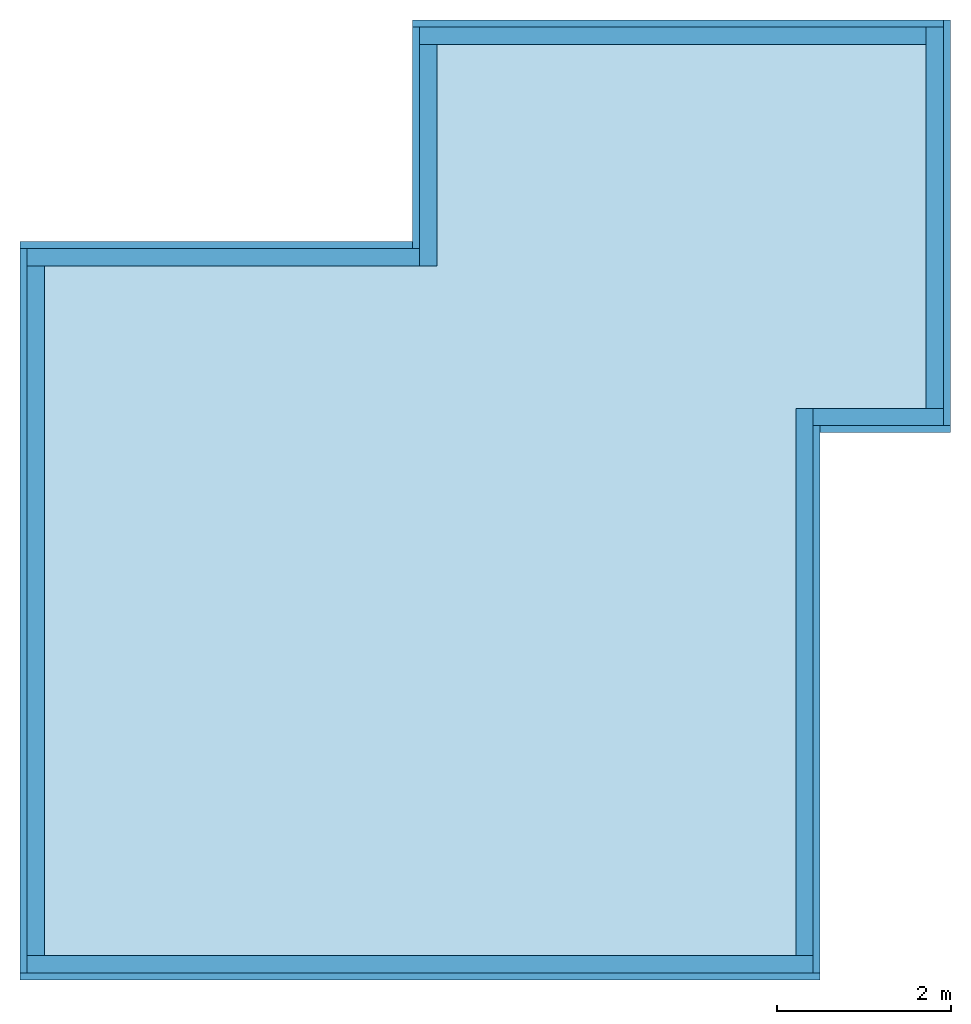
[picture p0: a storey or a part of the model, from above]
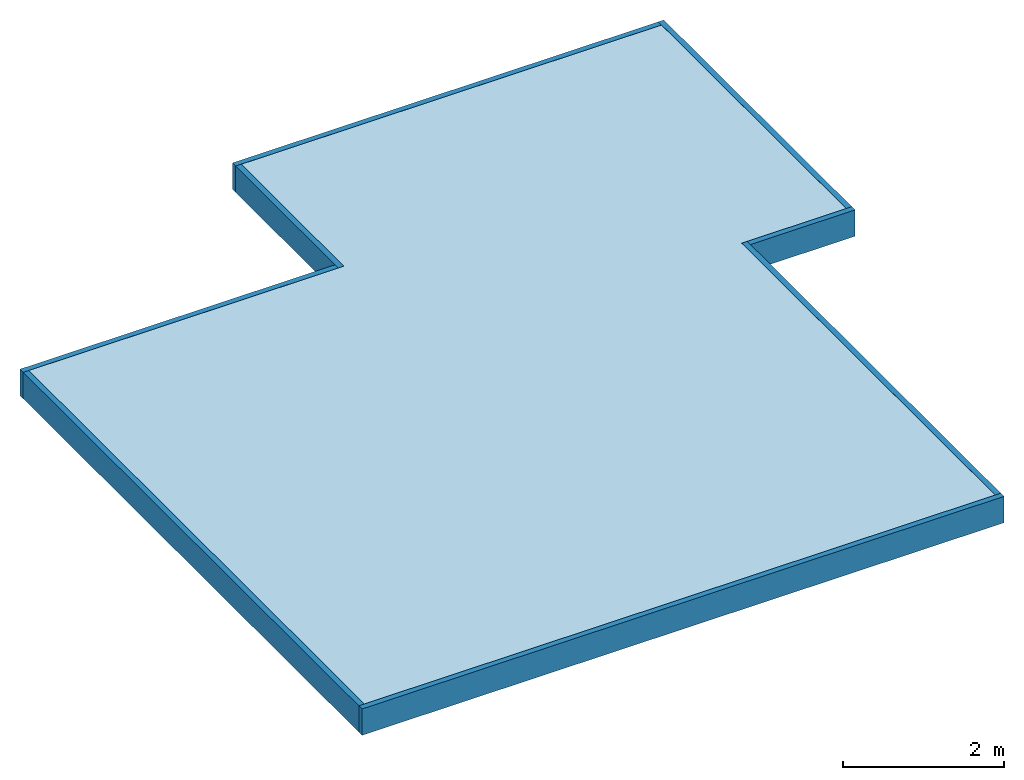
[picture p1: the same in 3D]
Properties of the parts of a building model (IFC2X3)

# File
Description: ViewDefinition [CoordinationView_V2.0, SurfaceGeometryAddOnView], Option [Drawing Scale: 50.000000], Option [Elements to export: Visible elements (on all stories)], Option [Partial Structure Display: Without Finishes], Option [IFC Domain: All], Option [Structural Function: All Elements], Option [Convert Grid elements: On], Option [Convert IFC Annotations and ARCHICAD 2D elements: Off], Option [Convert 2D symbols of Doors and Windows: Off], Option [Export geometries that Participates in Collision Detection only: On], Option [Split complex elements: Off], Option [Material Preservation: Never explode], Option [IFC Site Location: At Project Origin], Option [Curtain Wall export mode: Single Element], Option [Railing export mode: Single Element], Option [Stair export mode: Single Element], Option [Properties To Export: All properties], Option [Space containment: Off], Option [Bounding Box: Off], Option [Geometry to type objects: Off], Option [Element Properties: All], Option [Building Material Properties: Off], Option [Element Parameters: Off], Option [Component Parameters: Off], Option [IFC Base Quantities: Off], Option [Door Window Parameters: On], Option [IFC Space boundaries: Off], Option [ARCHICAD Zone Categories as IFC Space classification data: Off], Option [Element Classifications: Off]
File name: D:\Dane\Pulpit\TYMCZAAA\POINT_144_ARCH.ifc
Time: 2020-11-27T14:21:23
Author: Architect
Organization: Building Designer Office
Written by: The EXPRESS Data Manager Version 5.02.0100.09 : 26 Sep 2013
Made in: IFC file generated by GRAPHISOFT ARCHICAD 24.0.0 POL FULL Windows version (IFC add-on version: 3008 POL FULL).
Authorization: The authorising person

# IfcSite, Lokalizacja
RefLatitude: 52, 15, 0, 0; RefLongitude: 21, 0, 0, 0; RefElevation: 0 mm

# IfcBuildingStorey (4)
In: Budynek
Name | Elevation (mm)
PLATTE | -3000
EG | 0
DG | 2954
DACH | 5726

# IfcSpace: Ogólne (12)
InteriorOrExteriorSpace: INTERNAL
Pset_SpaceCommon - Category: Ogólne
AC_Pset_RenovationAndPhasing - Renovation Status: New
Name | In | _dan_NR | _dan_NAZWA | _dan_posadzka | _dan_Powierzchnia_DIN277 (m2)
 | EG | 1/1 | WC | FLIESEN | 3.93476
 | EG | 1/6 | GARDEROBE | FLIESEN | 3.60402
 | EG | 1/3 | WOHNEN-ESSEN | LAMINAT | 42.7011
 | EG | 1/4 | KÜCHE | FLIESEN | 8.137
 | EG | 1/5 | SPEIS | FLIESEN | 4.11435
 | EG | 1/7 | TECHNIKRAUM | FLIESEN | 6.52314
 | EG | 1/2 | DIELE | FLIESEN | 12.6479
 | DG | 2/5 | FLUR | TEPPICHBODEN | 8.24736
 | DG | 2/4 | BAD | FLIESEN | 8.37812
 | DG | 2/2 | ZIMMER 2 | TEPPICHBODEN | 16.068
 | DG | 2/3 | ZIMMER 3 | TEPPICHBODEN | 14.3588
 | DG | 2/1 | ZIMMER 1 | TEPPICHBODEN | 16.068

# IfcBeam: Drewno konstrukcyjne_elementy_konstrukcyjne 160 x 280 (2)
In: DACH
Material: Drewno konstrukcyjne_elementy_konstrukcyjne
_dan_Elem_Konstrukcyjny - _dan_Opis: Platew; _dan_Nazwa: Platew; _dan_Dlugosc: 10030 mm
AC_Pset_RenovationAndPhasing - Renovation Status: New
Pset_BeamCommon - Reference: Drewno konstrukcyjne_elementy_konstrukcyjne 160 x 280

# IfcBeam: Drewno konstrukcyjne_elementy_konstrukcyjne 180 x 180 (2)
In: DACH
Material: Drewno konstrukcyjne_elementy_konstrukcyjne
_dan_Elem_Konstrukcyjny - _dan_Opis: Platew_stopowa; _dan_Nazwa: Platew_stopowa; _dan_Dlugosc: 10030 mm
AC_Pset_RenovationAndPhasing - Renovation Status: New
Pset_BeamCommon - Reference: Drewno konstrukcyjne_elementy_konstrukcyjne 180 x 180

# IfcBeam: _DANWOOD_EL_KONSTR 170 x 220, UNTERZUG
In: EG
Material: _DANWOOD_EL_KONSTR
_dan_Elem_Konstrukcyjny - _dan_Opis: Podciag_widoczny_szer_170; _dan_Nazwa: UNTERZUG; _dan_Dlugosc: 4180 mm
AC_Pset_RenovationAndPhasing - Renovation Status: New
Pset_BeamCommon - Reference: _DANWOOD_EL_KONSTR 170 x 220

# IfcBeam: _DANWOOD_EL_KONSTR 230 x 220 (2)
In: EG
Material: _DANWOOD_EL_KONSTR
_dan_Elem_Konstrukcyjny - _dan_Opis: Podciag_widoczny_szer_230; _dan_Nazwa: UNTERZUG
AC_Pset_RenovationAndPhasing - Renovation Status: New
Pset_BeamCommon - Reference: _DANWOOD_EL_KONSTR 230 x 220
Name | _dan_Dlugosc (mm)
UNTERZUG | 2044.86
UNTERZUG | 1400

# IfcBuildingElementProxy: Suszarka do ubrań 24, OB5
In: EG
AC_Pset_RenovationAndPhasing - Renovation Status: New

# IfcDoor: Drzwi 24, D5
In: EG
Type - OperationType: SINGLE_SWING_LEFT; ParameterTakesPrecedence: no; Sizeable: no
Type - Door Lining Properties - LiningDepth: 100 mm; LiningThickness: 43 mm; ThresholdDepth: 200.1 mm; ThresholdThickness: 90 mm; LiningOffset: 240 mm; ThresholdOffset: 380.1 mm
Type - Door Panel Properties - Panel 1 - PanelDepth: 40 mm; PanelOperation: SWINGING; PanelWidth: 1; PanelPosition: MIDDLE
OverallHeight: 2210 mm; OverallWidth: 1090 mm
Pset_DoorCommon - ThermalTransmittance: 0
_dan_Drzwi - _dan_Opis: AUSSENTÜR; _dan_KierunekOtwierania: P; _dan_Styl: _dan_Zewn-Standard; _dan_Szerokosc: 1090 mm; _dan_Wysokosc: 2210 mm; _dan_GlebokoscRamy: 345 mm
AC_Pset_RenovationAndPhasing - Renovation Status: New

# IfcDoor: Drzwi 24, D5
In: DG
Type - OperationType: SINGLE_SWING_LEFT; ParameterTakesPrecedence: no; Sizeable: no
Type - Door Lining Properties - LiningDepth: 140 mm; LiningThickness: 20 mm; LiningOffset: -25 mm; CasingThickness: 60 mm; CasingDepth: 20 mm
Type - Door Panel Properties - Panel 1 - PanelDepth: 40 mm; PanelOperation: SWINGING; PanelWidth: 1; PanelPosition: MIDDLE
OverallHeight: 2010 mm; OverallWidth: 900 mm
Pset_DoorCommon - ThermalTransmittance: 0
_dan_Drzwi - _dan_Opis: TÜR 80; _dan_KierunekOtwierania: P; _dan_Styl: _dan_Wew_80; _dan_Szerokosc: 900 mm; _dan_Wysokosc: 2010 mm; _dan_GlebokoscRamy: 230 mm
AC_Pset_RenovationAndPhasing - Renovation Status: New

# IfcDoor: Drzwi 24, D5
In: DG
Type - OperationType: SINGLE_SWING_LEFT; ParameterTakesPrecedence: no; Sizeable: no
Type - Door Lining Properties - LiningDepth: 140 mm; LiningThickness: 20 mm; LiningOffset: 10 mm; CasingThickness: 60 mm; CasingDepth: 20 mm
Type - Door Panel Properties - Panel 1 - PanelDepth: 40 mm; PanelOperation: SWINGING; PanelWidth: 1; PanelPosition: MIDDLE
OverallHeight: 2010 mm; OverallWidth: 900 mm
Pset_DoorCommon - ThermalTransmittance: 0
_dan_Drzwi - _dan_Opis: TÜR 80; _dan_KierunekOtwierania: P; _dan_Styl: _dan_Wew_80; _dan_Szerokosc: 900 mm; _dan_Wysokosc: 2010 mm; _dan_GlebokoscRamy: 130 mm
AC_Pset_RenovationAndPhasing - Renovation Status: New

# IfcDoor: Drzwi 24, D4
In: DG
Type - OperationType: SINGLE_SWING_LEFT; ParameterTakesPrecedence: no; Sizeable: no
Type - Door Lining Properties - LiningDepth: 140 mm; LiningThickness: 20 mm; LiningOffset: 130 mm; CasingThickness: 60 mm; CasingDepth: 20 mm
Type - Door Panel Properties - Panel 1 - PanelDepth: 40 mm; PanelOperation: SWINGING; PanelWidth: 1; PanelPosition: MIDDLE
OverallHeight: 2010 mm; OverallWidth: 900 mm
Pset_DoorCommon - ThermalTransmittance: 0
_dan_Drzwi - _dan_Opis: TÜR 80; _dan_KierunekOtwierania: P; _dan_Styl: _dan_Wew_80; _dan_Szerokosc: 900 mm; _dan_Wysokosc: 2010 mm; _dan_GlebokoscRamy: 130 mm
AC_Pset_RenovationAndPhasing - Renovation Status: New

# IfcDoor: Drzwi 24, D4
In: DG
Type - OperationType: SINGLE_SWING_RIGHT; ParameterTakesPrecedence: no; Sizeable: no
Type - Door Lining Properties - LiningDepth: 140 mm; LiningThickness: 20 mm; LiningOffset: -25 mm; CasingThickness: 60 mm; CasingDepth: 20 mm
Type - Door Panel Properties - Panel 1 - PanelDepth: 40 mm; PanelOperation: SWINGING; PanelWidth: 1; PanelPosition: MIDDLE
OverallHeight: 2010 mm; OverallWidth: 900 mm
Pset_DoorCommon - ThermalTransmittance: 0
_dan_Drzwi - _dan_Opis: TÜR 80; _dan_KierunekOtwierania: L; _dan_Styl: _dan_Wew_80; _dan_Szerokosc: 900 mm; _dan_Wysokosc: 2010 mm; _dan_GlebokoscRamy: 230 mm
AC_Pset_RenovationAndPhasing - Renovation Status: New

# IfcDoor: Drzwi 24 (2)
In: EG
Type - OperationType: SINGLE_SWING_RIGHT; ParameterTakesPrecedence: no; Sizeable: no
Type - Door Lining Properties - LiningDepth: 140 mm; LiningThickness: 20 mm; LiningOffset: 10 mm; CasingThickness: 60 mm; CasingDepth: 20 mm
Type - Door Panel Properties - Panel 1 - PanelDepth: 40 mm; PanelOperation: SWINGING; PanelWidth: 1; PanelPosition: MIDDLE
OverallHeight: 2010 mm; OverallWidth: 900 mm
Pset_DoorCommon - ThermalTransmittance: 0
_dan_Drzwi - _dan_Opis: TÜR 80; _dan_KierunekOtwierania: L; _dan_Styl: _dan_Wew_80; _dan_Szerokosc: 900 mm; _dan_Wysokosc: 2010 mm; _dan_GlebokoscRamy: 130 mm
AC_Pset_RenovationAndPhasing - Renovation Status: New

# IfcDoor: Drzwi 24, D4
In: EG
Type - OperationType: SINGLE_SWING_RIGHT; ParameterTakesPrecedence: no; Sizeable: no
Type - Door Lining Properties - LiningDepth: 140 mm; LiningThickness: 20 mm; LiningOffset: 217 mm; CasingThickness: 60 mm; CasingDepth: 20 mm
Type - Door Panel Properties - Panel 1 - PanelDepth: 40 mm; PanelOperation: SWINGING; PanelWidth: 1; PanelPosition: MIDDLE
OverallHeight: 2010 mm; OverallWidth: 650 mm
Pset_DoorCommon - ThermalTransmittance: 0
_dan_Drzwi - _dan_Opis: TÜR 60; _dan_KierunekOtwierania: L; _dan_Styl: _dan_Wew_60; _dan_Szerokosc: 650 mm; _dan_Wysokosc: 2010 mm; _dan_GlebokoscRamy: 230 mm
AC_Pset_RenovationAndPhasing - Renovation Status: New

# IfcFlowTerminal: Brodzik prysznicowy 24, OB7
In: DG
Pset_FireRatingProperties - IsCombustible: no
Pset_ManufacturerOccurrence - BarCode: -
Pset_ManufacturerTypeInformation - ModelLabel: -
Ochrona przeciwpożarowa - Klasyfikacja ogniowa: -; Palność: no
Ochrona środowiska - Czas eksploatacji: 0; Zużycie energii: 0; Zmagazynowana energia: 0; Obciążenie w cyklu życia: 0; Certyfikat: Brak
Specyfikacja produktu - Model: -; Nr seryjny: -; Kod paskowy: -; Dostawca: -; Data zakupu: dd.mm.rrrr; Cena zakupu: 0; Producent: -; Data produkcji: dd.mm.rrrr; Gwarancja: dd.mm.rrrr; Kraj pochodzenia: -; Strona produktu: -; Kontakt: -
Kontakt - Osoba odpowiedzialna: -; Specjalność: -; Email: -; Telefon: -; Strona internetowa: -
AC_Pset_RenovationAndPhasing - Renovation Status: New

# IfcFlowTerminal: Umywalka 24 (2)
Pset_FireRatingProperties - IsCombustible: no
Pset_ManufacturerOccurrence - BarCode: -
Pset_ManufacturerTypeInformation - ModelLabel: -
Ochrona przeciwpożarowa - Klasyfikacja ogniowa: -; Palność: no
Ochrona środowiska - Czas eksploatacji: 0; Zużycie energii: 0; Zmagazynowana energia: 0; Obciążenie w cyklu życia: 0; Certyfikat: Brak
Specyfikacja produktu - Model: -; Nr seryjny: -; Kod paskowy: -; Dostawca: -; Data zakupu: dd.mm.rrrr; Cena zakupu: 0; Producent: -; Data produkcji: dd.mm.rrrr; Gwarancja: dd.mm.rrrr; Kraj pochodzenia: -; Strona produktu: -; Kontakt: -
Kontakt - Osoba odpowiedzialna: -; Specjalność: -; Email: -; Telefon: -; Strona internetowa: -
AC_Pset_RenovationAndPhasing - Renovation Status: New
Name | In
OB5 | EG
OB5 | DG

# IfcFlowTerminal: WC 24 (2)
Pset_FireRatingProperties - IsCombustible: no
Pset_ManufacturerOccurrence - BarCode: -
Pset_ManufacturerTypeInformation - ModelLabel: -
Ochrona przeciwpożarowa - Klasyfikacja ogniowa: -; Palność: no
Ochrona środowiska - Czas eksploatacji: 0; Zużycie energii: 0; Zmagazynowana energia: 0; Obciążenie w cyklu życia: 0; Certyfikat: Brak
Specyfikacja produktu - Model: -; Nr seryjny: -; Kod paskowy: -; Dostawca: -; Data zakupu: dd.mm.rrrr; Cena zakupu: 0; Producent: -; Data produkcji: dd.mm.rrrr; Gwarancja: dd.mm.rrrr; Kraj pochodzenia: -; Strona produktu: -; Kontakt: -
Kontakt - Osoba odpowiedzialna: -; Specjalność: -; Email: -; Telefon: -; Strona internetowa: -
AC_Pset_RenovationAndPhasing - Renovation Status: New
Name | In
OB5 | EG
OB5 | DG

# IfcFlowTerminal: Wanna 24, OB5
In: DG
Pset_FireRatingProperties - IsCombustible: no
Pset_ManufacturerOccurrence - BarCode: -
Pset_ManufacturerTypeInformation - ModelLabel: -
Ochrona przeciwpożarowa - Klasyfikacja ogniowa: -; Palność: no
Ochrona środowiska - Czas eksploatacji: 0; Zużycie energii: 0; Zmagazynowana energia: 0; Obciążenie w cyklu życia: 0; Certyfikat: Brak
Specyfikacja produktu - Model: -; Nr seryjny: -; Kod paskowy: -; Dostawca: -; Data zakupu: dd.mm.rrrr; Cena zakupu: 0; Producent: -; Data produkcji: dd.mm.rrrr; Gwarancja: dd.mm.rrrr; Kraj pochodzenia: -; Strona produktu: -; Kontakt: -
Kontakt - Osoba odpowiedzialna: -; Specjalność: -; Email: -; Telefon: -; Strona internetowa: -
AC_Pset_RenovationAndPhasing - Renovation Status: New

# IfcSlab: 031- _dan_Strop_2 276, P1
In: DG
Type - PredefinedType: FLOOR
Material: Płyta OSB, Drewno konstrukcyjne, Drewno montażowe, Płyta GK
_dan_Strop - _dan_Styl: _dan_Strop2
AC_Pset_RenovationAndPhasing - Renovation Status: New
Pset_SlabCommon - LoadBearing: yes; IsExternal: no

# IfcSlab: 033- _dan_Strop_3 254, P1
In: DACH
Type - PredefinedType: FLOOR
Material: Drewno konstrukcyjne, Płyta OSB, Płyta GK
_dan_Strop - _dan_Styl: _dan_Strop3
AC_Pset_RenovationAndPhasing - Renovation Status: New
Pset_SlabCommon - LoadBearing: yes; IsExternal: no

# IfcSlab: 041- _dan_Panel 394 (2)
In: DACH
Type - PredefinedType: ROOF
Material: Beton, Drewno montażowe (2), Drewno konstrukcyjne dach, Płyta OSB, Płyta GK
_dan_PolacDachowa - _dan_Nachylenie: 30 deg; _dan_Styl: _dan_Panel; _dan_PowierzchniaCalkowita: 56.1098 m2; _dan_PowierzchnianeNetto: 56.1098 m2
AC_Pset_RenovationAndPhasing - Renovation Status: New
Pset_SlabCommon - LoadBearing: no; IsExternal: yes

# IfcSlab: 071- _dan_Strop2_CUBE 276, P1
In: DG
Type - PredefinedType: FLOOR
Material: Płyta OSB, Drewno konstrukcyjne, Drewno montażowe, Płyta GK
_dan_Strop - _dan_Styl: _dan_Strop2_CUBE
AC_Pset_RenovationAndPhasing - Renovation Status: New
Pset_SlabCommon - LoadBearing: yes; IsExternal: no

# IfcSlab: 091 - dan Płyta fundamentowa 250, P1
In: PLATTE
Type - PredefinedType: FLOOR
Material: ----KONSTRUKCYJNE, ---- IZOLACYJNE 400 ------------
_dan_Strop - _dan_Styl: _dan_Platte
AC_Pset_RenovationAndPhasing - Renovation Status: New
Pset_SlabCommon - LoadBearing: yes; IsExternal: no

# IfcSlab: Płyty styropianowe miękkie 264, P1
In: DG
Type - PredefinedType: FLOOR
Material: Płyty styropianowe miękkie
_dan_Strop - _dan_Styl: Wypelnienie_styropian_strop
AC_Pset_RenovationAndPhasing - Renovation Status: New
Pset_SlabCommon - LoadBearing: no; IsExternal: yes

# IfcWall: 002- _dan_SZ_345 345 (12)
_dan_Sciana - _dan_Styl: _dan_SZ_345
AC_Pset_RenovationAndPhasing - Renovation Status: New
Name | In | Material | _dan_Wysokosc (mm) | _dan_Dlugosc (mm)
SZ1 | EG | Płyta GK, Płyta OSB (2), Drewno konstrukcyjne, Płyty styropianowe miękkie | 2690 | 1500
SZ1 | EG | Płyty styropianowe miękkie, Płyta OSB (2), Drewno konstrukcyjne, Płyta GK | 2690 | 4180
SZ1 | EG | Płyty styropianowe miękkie, Płyta OSB (2), Drewno konstrukcyjne, Płyta GK | 2690 | 5620
SZ1 | EG | Płyta GK, Płyta OSB (2), Drewno konstrukcyjne, Płyty styropianowe miękkie | 2690 | 2550
SZ1 | EG | Płyty styropianowe miękkie, Płyta OSB (2), Drewno konstrukcyjne, Płyta GK | 2690 | 4520
SZ1 | EG | Płyta GK, Płyta OSB (2), Drewno konstrukcyjne, Płyty styropianowe miękkie | 2690 | 8640
SZ1 | EG | Płyty styropianowe miękkie, Płyta OSB (2), Drewno konstrukcyjne, Płyta GK | 2690 | 7930
SZ1 | EG | Płyta GK, Płyta OSB (2), Drewno konstrukcyjne, Płyty styropianowe miękkie | 2690 | 6300
SZ2 | DG | Płyta GK, Płyta OSB (2), Drewno konstrukcyjne, Płyty styropianowe miękkie | 1699.26 | 8640
SZ2 | DG | Płyty styropianowe miękkie, Płyta OSB (2), Drewno konstrukcyjne, Płyta GK | 1699.26 | 8640
SZ2 | DG | Płyta GK, Płyta OSB (2), Drewno konstrukcyjne, Płyty styropianowe miękkie | 3988.45 | 7930
SZ2 | DG | Płyty styropianowe miękkie, Płyta OSB (2), Drewno konstrukcyjne, Płyta GK | 3988.45 | 7930

# IfcWall: 003- _dan_SZA_332 332 (4)
In: DG
_dan_Sciana - _dan_Styl: _dan_SA_332; _dan_Wysokosc: 500 mm
AC_Pset_RenovationAndPhasing - Renovation Status: New
Name | Material | _dan_Dlugosc (mm)
SZ2 | Płyty styropianowe miękkie, Płyta OSB (2), Drewno konstrukcyjne_attyka | 2218
SZ2 | Płyty styropianowe miękkie, Płyta OSB (2), Drewno konstrukcyjne_attyka | 5646
SZ2 | Płyta OSB (2), Drewno konstrukcyjne_attyka, Płyty styropianowe miękkie | 4206
SZ2 | Płyta OSB (2), Drewno konstrukcyjne_attyka, Płyty styropianowe miękkie | 1168

# IfcWall: 022- _dan_SD_130 130 (8)
Material: Płyta GK (2), Płyta OSB (2), Drewno konstrukcyjne
_dan_Sciana - _dan_Styl: _dan_SD_130; _dan_Wysokosc: 2690 mm
AC_Pset_RenovationAndPhasing - Renovation Status: New
Name | In | _dan_Dlugosc (mm)
SW1 | EG | 4249.86
SW1 | EG | 1830
SW1 | EG | 2044.86
SW1 | EG | 2230
SW1 | DG | 1245.21
SW1 | DG | 984.787
SW1 | DG | 4120
SW1 | DG | 3241.86

# IfcWall: 025- _dan_SW_230 230 (8)
Material: Płyta GK (2), Płyta OSB (2), Drewno konstrukcyjne
_dan_Sciana - _dan_Styl: _dan_SW_230; _dan_Wysokosc: 2690 mm
AC_Pset_RenovationAndPhasing - Renovation Status: New
Name | In | _dan_Dlugosc (mm)
SW4 | EG | 2150.14
SW4 | EG | 1460
SW4 | EG | 1930
SW4 | EG | 2280.14
SW4 | EG | 1975
SW4 | DG | 7930
SW4 | DG | 2018.14
SW4 | DG | 2914.79

# IfcWall: 026- _dan_SW_245 245, SW4
In: DG
Material: Drewno konstrukcyjne, Płyta OSB, Płyta GK
_dan_Sciana - _dan_Styl: _dan_SW_245; _dan_Wysokosc: 2690 mm; _dan_Dlugosc: 1830 mm
AC_Pset_RenovationAndPhasing - Renovation Status: New

# IfcWall: 401- dan SF - DE 280 (8)
In: PLATTE
Material: ----KONSTRUKCYJNE, ---- IZOLACYJNE 400 ------------
_dan_Sciana - _dan_Styl: _dan_Platte; _dan_Wysokosc: 400 mm
AC_Pset_RenovationAndPhasing - Renovation Status: New
Name | _dan_Dlugosc (mm)
SW2 | 8649.97
SW3 | 6300
SW3 | 1500
SW4 | 4190
SW5 | 5629.97
SW6 | 2550
SW7 | 4520
SW8 | 7940

# IfcWall: Zakończenie zamknięte 24 (4)
In: EG
Material: Płyta GK
_dan_Sciana - _dan_Styl: _dan_zabudowa; _dan_Wysokosc: 2678 mm
AC_Pset_RenovationAndPhasing - Renovation Status: New
Name
ZS5
2 x ZS4
ZS6

# IfcWindow: Okno 24
In: DG
Type - OperationType: SINGLE_PANEL; ParameterTakesPrecedence: no; Sizeable: no
Type - Window Lining Properties - LiningDepth: 96 mm; LiningThickness: 60 mm
Type - Window Panel Properties - Panel 1 - OperationType: BOTTOMHUNG; PanelPosition: MIDDLE; FrameDepth: 60 mm; FrameThickness: 60 mm
OverallHeight: 625 mm; OverallWidth: 1500 mm
Pset_WindowCommon - ThermalTransmittance: 0; GlazingAreaFraction: 0.44424
_dan_Okno - _dan_TYP: F18; _dan_GROSSE: 1 480 x 605; _dan_ROLLADEN: .; _dan_BESCHREIBUNG: VSG; _dan_BESCHREIBUNG2: Max Offnungsmass 12cm; _dan_Szerokosc: 1480 mm; _dan_Wysokosc: 605 mm
AC_Pset_RenovationAndPhasing - Renovation Status: New

# IfcWindow: Okno 24 (4)
Type - OperationType: SINGLE_PANEL; ParameterTakesPrecedence: no; Sizeable: no
Type - Window Lining Properties - LiningDepth: 96 mm; LiningThickness: 60 mm
Type - Window Panel Properties - Panel 1 - OperationType: FIXEDCASEMENT; PanelPosition: MIDDLE; FrameDepth: 60 mm; FrameThickness: 60 mm
Pset_WindowCommon - ThermalTransmittance: 0
_dan_Okno - _dan_ROLLADEN: .
AC_Pset_RenovationAndPhasing - Renovation Status: New
Name | In | OverallHeight (mm) | OverallWidth (mm) | GlazingAreaFraction | _dan_TYP | _dan_GROSSE | _dan_Szerokosc (mm) | _dan_Wysokosc (mm)
 | EG | 2135 | 2750 | 4.65219 | FIX183 | 2 730 x 2 115 | 2730 | 2115
 | EG | 2135 | 2000 | 3.25104 | FIX149 | 1 980 x 2 115 | 1980 | 2115
2 x  | DG | 625 | 2250 | 0.71289 | FIX195 | 2 230 x 605 | 2230 | 605 | _dan_Okno - _dan_BESCHREIBUNG: VSG

# IfcWindow: Okno 24 (2)
In: EG
Type - OperationType: SINGLE_PANEL; ParameterTakesPrecedence: no; Sizeable: no
Type - Window Lining Properties - LiningDepth: 96 mm; LiningThickness: 60 mm
Type - Window Panel Properties - Panel 1 - OperationType: TILTANDTURNLEFTHAND; PanelPosition: MIDDLE; FrameDepth: 60 mm; FrameThickness: 60 mm
OverallHeight: 2135 mm
Pset_WindowCommon - ThermalTransmittance: 0
_dan_Okno - _dan_ROLLADEN: .; _dan_Orientacja: L; _dan_Wysokosc: 2115 mm
AC_Pset_RenovationAndPhasing - Renovation Status: New
Name | OverallWidth (mm) | GlazingAreaFraction | _dan_TYP | _dan_GROSSE | _dan_Szerokosc (mm)
 | 1000 | 1.38284 | F54 | 980 x 2 115 | 980
 | 625 | 0.682267 | F83 | 605 x 2 115 | 605

# IfcWindow: Okno 24 (2)
In: EG
Type - OperationType: SINGLE_PANEL; ParameterTakesPrecedence: no; Sizeable: no
Type - Window Lining Properties - LiningDepth: 96 mm; LiningThickness: 60 mm
Type - Window Panel Properties - Panel 1 - OperationType: TILTANDTURNRIGHTHAND; PanelPosition: MIDDLE; FrameDepth: 60 mm; FrameThickness: 60 mm
OverallHeight: 2135 mm
Pset_WindowCommon - ThermalTransmittance: 0
_dan_Okno - _dan_ROLLADEN: .; _dan_Orientacja: P; _dan_Wysokosc: 2115 mm
AC_Pset_RenovationAndPhasing - Renovation Status: New
Name | OverallWidth (mm) | GlazingAreaFraction | _dan_TYP | _dan_GROSSE | _dan_Szerokosc (mm)
 | 625 | 0.682267 | F82 | 605 x 2 115 | 605
 | 1000 | 1.38284 | F53 | 980 x 2 115 | 980

# IfcWindow: Okno nietypowe 24
In: DG
Type - OperationType: DOUBLE_PANEL_HORIZONTAL; ParameterTakesPrecedence: no; Sizeable: no
Type - Window Lining Properties - LiningDepth: 96 mm; LiningThickness: 60 mm; TransomThickness: 60 mm; FirstTransomOffset: 0.349882
Type - Window Panel Properties - Panel 1 - OperationType: TILTANDTURNRIGHTHAND; PanelPosition: TOP; FrameDepth: 60 mm; FrameThickness: 60 mm
Type - Window Panel Properties - Panel 2 - OperationType: FIXEDCASEMENT; PanelPosition: BOTTOM
OverallHeight: 2135 mm; OverallWidth: 1090 mm
Pset_WindowCommon - ThermalTransmittance: 0; GlazingAreaFraction: 1.596
_dan_Okno - _dan_TYP: FLUCHTFENSTER 11; _dan_GROSSE: 1 070 x 2 115; _dan_ROLLADEN: .; _dan_Orientacja: P; _dan_Szerokosc: 1070 mm; _dan_Wysokosc: 2115 mm
AC_Pset_RenovationAndPhasing - Renovation Status: New

# IfcWindow: Okno nietypowe 24
In: DG
Type - OperationType: DOUBLE_PANEL_HORIZONTAL; ParameterTakesPrecedence: no; Sizeable: no
Type - Window Lining Properties - LiningDepth: 96 mm; LiningThickness: 60 mm; TransomThickness: 60 mm; FirstTransomOffset: 0.449173
Type - Window Panel Properties - Panel 1 - OperationType: TILTANDTURNLEFTHAND; PanelPosition: TOP; FrameDepth: 60 mm; FrameThickness: 60 mm
Type - Window Panel Properties - Panel 2 - OperationType: FIXEDCASEMENT; PanelPosition: BOTTOM
OverallHeight: 2135 mm; OverallWidth: 1000 mm
Pset_WindowCommon - ThermalTransmittance: 0; GlazingAreaFraction: 1.45662
_dan_Okno - _dan_TYP: F54/1; _dan_GROSSE: 980 x 2 115; _dan_ROLLADEN: .; _dan_Orientacja: L; _dan_Szerokosc: 980 mm; _dan_Wysokosc: 2115 mm
AC_Pset_RenovationAndPhasing - Renovation Status: New

# IfcWindow: Okno nietypowe 24 (2)
In: DG
Type - OperationType: DOUBLE_PANEL_HORIZONTAL; ParameterTakesPrecedence: no; Sizeable: no
Type - Window Lining Properties - LiningDepth: 96 mm; LiningThickness: 60 mm; TransomThickness: 60 mm; FirstTransomOffset: 0.449173
Type - Window Panel Properties - Panel 1 - OperationType: TILTANDTURNRIGHTHAND; PanelPosition: TOP; FrameDepth: 60 mm; FrameThickness: 60 mm
Type - Window Panel Properties - Panel 2 - OperationType: FIXEDCASEMENT; PanelPosition: BOTTOM
OverallHeight: 2135 mm
Pset_WindowCommon - ThermalTransmittance: 0
_dan_Okno - _dan_ROLLADEN: .; _dan_Orientacja: P; _dan_Wysokosc: 2115 mm
AC_Pset_RenovationAndPhasing - Renovation Status: New
Name | OverallWidth (mm) | GlazingAreaFraction | _dan_TYP | _dan_GROSSE | _dan_Szerokosc (mm)
 | 1125 | 1.68515 | F57/1 | 1 105 x 2 115 | 1105
 | 1000 | 1.45662 | F53/1 | 980 x 2 115 | 980

# IfcWindow: Okno podwójne 24
In: EG
Type - OperationType: DOUBLE_PANEL_VERTICAL; ParameterTakesPrecedence: no; Sizeable: no
Type - Window Lining Properties - LiningDepth: 96 mm; LiningThickness: 60 mm; MullionThickness: 60 mm; FirstMullionOffset: 0.591928
Type - Window Panel Properties - Panel 1 - OperationType: TILTANDTURNLEFTHAND; PanelPosition: RIGHT; FrameDepth: 60 mm; FrameThickness: 60 mm
Type - Window Panel Properties - Panel 2 - OperationType: FIXEDCASEMENT; PanelPosition: LEFT
OverallHeight: 2135 mm; OverallWidth: 2250 mm
Pset_WindowCommon - ThermalTransmittance: 0; GlazingAreaFraction: 3.75335
_dan_Okno - _dan_TYP: F500P; _dan_GROSSE: 2 230 x 2 115; _dan_ROLLADEN: .; _dan_Orientacja: L; _dan_Szerokosc: 2230 mm; _dan_Wysokosc: 2115 mm
AC_Pset_RenovationAndPhasing - Renovation Status: New

# IfcWindow: Okno podwójne 24
In: EG
Type - OperationType: DOUBLE_PANEL_VERTICAL; ParameterTakesPrecedence: no; Sizeable: no
Type - Window Lining Properties - LiningDepth: 96 mm; LiningThickness: 60 mm; MullionThickness: 60 mm; FirstMullionOffset: 0.612108
Type - Window Panel Properties - Panel 1 - OperationType: TILTANDTURNLEFTHAND; PanelPosition: RIGHT; FrameDepth: 60 mm; FrameThickness: 60 mm
Type - Window Panel Properties - Panel 2 - OperationType: BOTTOMHUNG; PanelPosition: LEFT; FrameDepth: 60 mm; FrameThickness: 60 mm
OverallHeight: 625 mm; OverallWidth: 2250 mm
Pset_WindowCommon - ThermalTransmittance: 0; GlazingAreaFraction: 0.669906
_dan_Okno - _dan_TYP: F17/1; _dan_GROSSE: 2 230 x 605; _dan_ROLLADEN: .; _dan_Szerokosc: 2230 mm; _dan_Wysokosc: 605 mm
AC_Pset_RenovationAndPhasing - Renovation Status: New

# IfcWindow: Okno podwójne 24
In: EG
Type - OperationType: DOUBLE_PANEL_VERTICAL; ParameterTakesPrecedence: no; Sizeable: no
Type - Window Lining Properties - LiningDepth: 96 mm; LiningThickness: 60 mm; MullionThickness: 60 mm; FirstMullionOffset: 0.623318
Type - Window Panel Properties - Panel 1 - OperationType: TILTANDTURNLEFTHAND; PanelPosition: RIGHT; FrameDepth: 60 mm; FrameThickness: 60 mm
Type - Window Panel Properties - Panel 2 - OperationType: FIXEDCASEMENT; PanelPosition: LEFT; FrameDepth: 60 mm; FrameThickness: 60 mm
OverallHeight: 1125 mm; OverallWidth: 2250 mm
Pset_WindowCommon - ThermalTransmittance: 0; GlazingAreaFraction: 1.60501
_dan_Okno - _dan_TYP: F260/1P; _dan_GROSSE: 2 230 x 1 105; _dan_ROLLADEN: .; _dan_Szerokosc: 2230 mm; _dan_Wysokosc: 1105 mm
AC_Pset_RenovationAndPhasing - Renovation Status: New
